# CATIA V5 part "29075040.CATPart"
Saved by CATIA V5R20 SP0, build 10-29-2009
Part number: 29075040
Definition: NONE
Nomenclature: 29075040
Source: Unknown
Description: 29075040
Bounding box of the stored display mesh (mm): x -20 to 44.548, y -51.5 to 86.048, z -41.5 to 41.5
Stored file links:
  C:\Users\Utente\Desktop\IO LAVORO\3D X SITO CF\X SITO\PLASTICA\RF1\29075040.CATPart

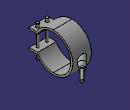
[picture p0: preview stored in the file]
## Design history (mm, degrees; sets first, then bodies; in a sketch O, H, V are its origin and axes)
Body1 "29075040" (main body)
  Solid1: solid without history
